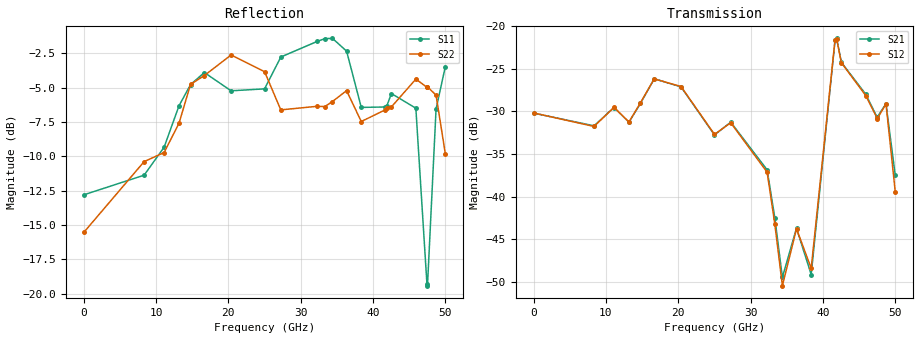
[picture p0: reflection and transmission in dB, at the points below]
!Keysight Technologies,N5245B,MY58422270,A.16.20.02
!Date: Thursday, March 05, 2026 01:42:45
!Correction: S11(C  2-Port  )
!S21(C  2-Port  )
!S12(C  2-Port  )
!S22(C  2-Port  )
!S2P File: Measurements: S11, S21, S12, S22:
# Hz S  dB  R 50
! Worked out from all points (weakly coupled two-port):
!   3201 points, 10 MHz to 50 GHz, reference 50 ohm
!   highest |S21| = -21.45 dB at 41.89 GHz (marker M1); lowest = -49.5 dB at 34.39 GHz (marker M2)
!   lowest |S11| = -19.4 dB at 47.53 GHz (marker M3), VSWR 1.24, Z = 45.6 + j9.3 ohm
!   |S11| at or under -10 dB: start of sweep to 10.03 GHz; 11.36 GHz to 11.93 GHz (573.5 MHz wide, 4.92 % of centre); 46.68 GHz to 48.24 GHz (1.555 GHz wide, 3.28 % of centre)
!   |S22| runs from -19.9 to -2.5 dB; largest |S21 - S12| = 0.0038
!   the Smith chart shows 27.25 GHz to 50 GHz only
!   S11 on the Smith chart (normalised r, x): 27.25 GHz: 0.18, +0.36; 32.28 GHz: 0.42, +1.84; 36.35 GHz: 2.44, -3.42; 42.55 GHz: 0.95, -1.23; 47.45 GHz: 0.86, +0.15; 50 GHz: 0.63, -1.39
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1e7  -12.80 -3.0  -30.22 0.6  -30.20 7.7  -15.54 42.0
8.352081e9  -11.37 174.9  -31.71 35.5  -31.78 35.3  -10.38 -175.5
1.111715e10  -9.33 107.2  -29.56 -59.8  -29.54 -60.1  -9.72 84.4
1.317924e10  -6.31 63.1  -31.28 -112.0  -31.26 -112.1  -7.58 -22.8
1.477267e10  -4.77 12.3  -29.08 -145.1  -29.01 -145.0  -4.75 -91.4
1.667854e10  -3.89 -43.9  -26.19 159.6  -26.20 159.6  -4.11 -142.5
2.038092e10  -5.22 -121.1  -27.14 41.1  -27.10 41.3  -2.61 153.6
2.5005e10  -5.08 -178.9  -32.78 -65.2  -32.71 -65.9  -3.83 71.1
2.725455e10  -2.76 139.3  -31.28 -113.7  -31.35 -113.5  -6.61 31.8
3.228479e10  -1.62 55.1  -36.87 46.9  -37.15 48.6  -6.35 -105.2
3.334708e10  -1.42 36.0  -42.49 -0.2  -43.22 -2.4  -6.37 -129.6
3.439375e10  -1.40 17.3  -49.48 -93.6  -50.46 -100.4  -6.00 -152.5
3.634648e10  -2.33 -22.3  -43.72 111.1  -43.79 115.0  -5.21 169.9
3.837732e10  -6.43 -22.4  -49.15 -109.0  -48.42 -113.2  -7.46 137.7
4.167354e10  -6.40 -53.0  -21.68 -54.8  -21.63 -54.8  -6.61 112.4
4.189225e10  -6.34 -52.9  -21.45 -75.3  -21.48 -75.5  -6.46 110.4
4.254837e10  -5.42 -60.0  -24.26 -118.4  -24.31 -119.5  -6.39 107.3
4.592269e10  -6.49 -116.6  -28.00 47.1  -28.16 47.2  -4.37 62.4
4.745363e10  -19.27 128.0  -30.64 -9.5  -30.74 -9.7  -4.96 43.5
4.753174e10  -19.42 109.6  -30.65 -10.1  -30.85 -10.4  -4.93 42.7
4.871901e10  -6.54 -22.0  -29.12 -86.1  -29.13 -84.6  -5.54 20.0
5e10  -3.46 -64.6  -37.50 -135.6  -39.43 -132.2  -9.81 7.2
